VERSION 5.8 ;
BUSBITCHARS "[]" ;
DIVIDERCHAR "/" ;
UNITS
    DATABASE MICRONS 1000 ;
END UNITS

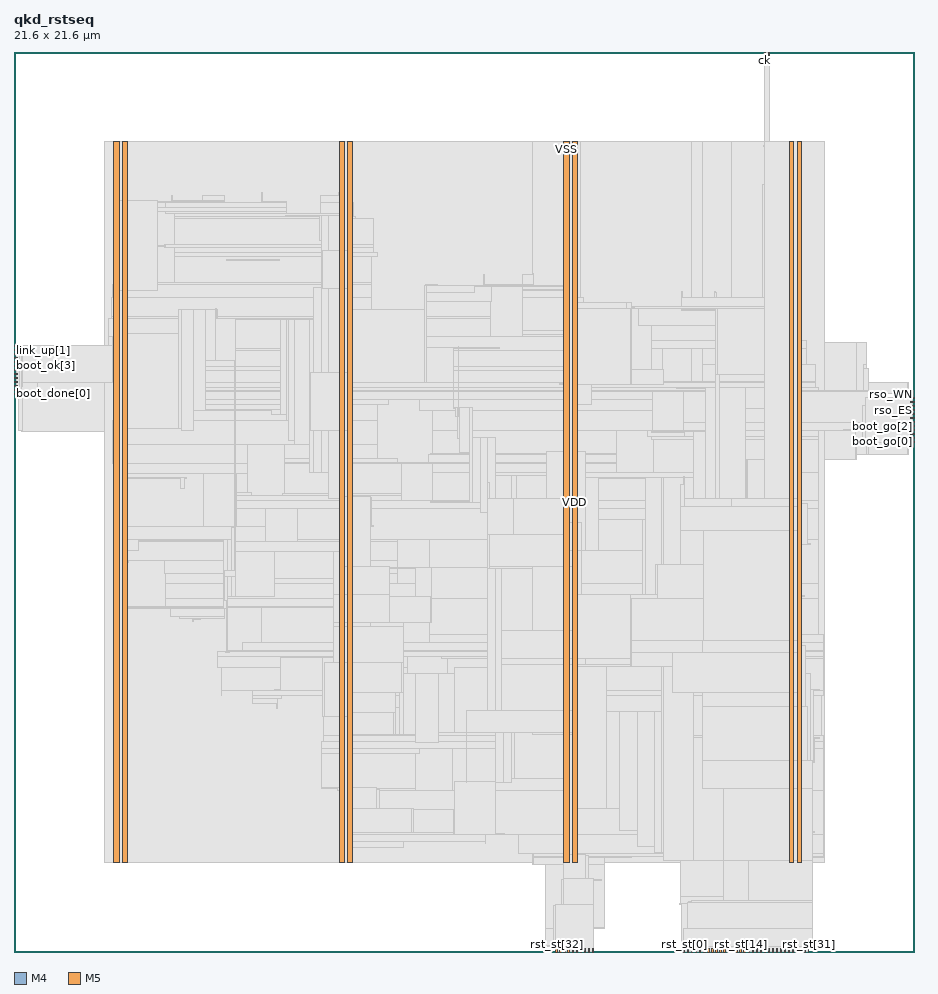
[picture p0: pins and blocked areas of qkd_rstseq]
MACRO qkd_rstseq
  FOREIGN qkd_rstseq 0 0 ;
  CLASS BLOCK ;
  SIZE 21.6 BY 21.6 ;
  PIN boot_done[0]
    DIRECTION INPUT ;
    USE SIGNAL ;
    PORT
      LAYER M4 ;
        RECT  0 13.392 0.084 13.416 ;
    END
  END boot_done[0]
  PIN boot_done[1]
    DIRECTION INPUT ;
    USE SIGNAL ;
    PORT
      LAYER M4 ;
        RECT  0 13.488 0.084 13.512 ;
    END
  END boot_done[1]
  PIN boot_done[2]
    DIRECTION INPUT ;
    USE SIGNAL ;
    PORT
      LAYER M4 ;
        RECT  0 13.584 0.084 13.608 ;
    END
  END boot_done[2]
  PIN boot_done[3]
    DIRECTION INPUT ;
    USE SIGNAL ;
    PORT
      LAYER M4 ;
        RECT  0 13.68 0.084 13.704 ;
    END
  END boot_done[3]
  PIN boot_go[0]
    DIRECTION OUTPUT ;
    USE SIGNAL ;
    PORT
      LAYER M4 ;
        RECT  21.516 12.24 21.6 12.264 ;
    END
  END boot_go[0]
  PIN boot_go[1]
    DIRECTION OUTPUT ;
    USE SIGNAL ;
    PORT
      LAYER M4 ;
        RECT  21.516 12.336 21.6 12.36 ;
    END
  END boot_go[1]
  PIN boot_go[2]
    DIRECTION OUTPUT ;
    USE SIGNAL ;
    PORT
      LAYER M4 ;
        RECT  21.516 12.432 21.6 12.456 ;
    END
  END boot_go[2]
  PIN boot_go[3]
    DIRECTION OUTPUT ;
    USE SIGNAL ;
    PORT
      LAYER M4 ;
        RECT  21.516 12.528 21.6 12.552 ;
    END
  END boot_go[3]
  PIN boot_ok[0]
    DIRECTION INPUT ;
    USE SIGNAL ;
    PORT
      LAYER M4 ;
        RECT  0 13.776 0.084 13.8 ;
    END
  END boot_ok[0]
  PIN boot_ok[1]
    DIRECTION INPUT ;
    USE SIGNAL ;
    PORT
      LAYER M4 ;
        RECT  0 13.872 0.084 13.896 ;
    END
  END boot_ok[1]
  PIN boot_ok[2]
    DIRECTION INPUT ;
    USE SIGNAL ;
    PORT
      LAYER M4 ;
        RECT  0 13.968 0.084 13.992 ;
    END
  END boot_ok[2]
  PIN boot_ok[3]
    DIRECTION INPUT ;
    USE SIGNAL ;
    PORT
      LAYER M4 ;
        RECT  0 14.064 0.084 14.088 ;
    END
  END boot_ok[3]
  PIN ck
    DIRECTION INPUT ;
    USE SIGNAL ;
    PORT
      LAYER M5 ;
        RECT  18 21.516 18.024 21.6 ;
    END
  END ck
  PIN link_up[0]
    DIRECTION INPUT ;
    USE SIGNAL ;
    PORT
      LAYER M4 ;
        RECT  0 14.16 0.084 14.184 ;
    END
  END link_up[0]
  PIN link_up[1]
    DIRECTION INPUT ;
    USE SIGNAL ;
    PORT
      LAYER M4 ;
        RECT  0 14.256 0.084 14.28 ;
    END
  END link_up[1]
  PIN link_up[2]
    DIRECTION INPUT ;
    USE SIGNAL ;
    PORT
      LAYER M4 ;
        RECT  0 14.352 0.084 14.376 ;
    END
  END link_up[2]
  PIN link_up[3]
    DIRECTION INPUT ;
    USE SIGNAL ;
    PORT
      LAYER M4 ;
        RECT  0 14.448 0.084 14.472 ;
    END
  END link_up[3]
  PIN por_n
    DIRECTION INPUT ;
    USE SIGNAL ;
    PORT
      LAYER M5 ;
        RECT  18.096 21.516 18.12 21.6 ;
    END
  END por_n
  PIN rso_EN
    DIRECTION OUTPUT ;
    USE SIGNAL ;
    PORT
      LAYER M4 ;
        RECT  21.516 12.72 21.6 12.744 ;
    END
  END rso_EN
  PIN rso_ES
    DIRECTION OUTPUT ;
    USE SIGNAL ;
    PORT
      LAYER M4 ;
        RECT  21.516 12.816 21.6 12.84 ;
    END
  END rso_ES
  PIN rso_WN
    DIRECTION OUTPUT ;
    USE SIGNAL ;
    PORT
      LAYER M4 ;
        RECT  21.516 13.2 21.6 13.224 ;
    END
  END rso_WN
  PIN rso_WS
    DIRECTION OUTPUT ;
    USE SIGNAL ;
    PORT
      LAYER M4 ;
        RECT  21.516 13.296 21.6 13.32 ;
    END
  END rso_WS
  PIN rso_c
    DIRECTION OUTPUT ;
    USE SIGNAL ;
    PORT
      LAYER M4 ;
        RECT  21.516 12.624 21.6 12.648 ;
    END
  END rso_c
  PIN rso_fwd
    DIRECTION OUTPUT ;
    USE SIGNAL ;
    PORT
      LAYER M4 ;
        RECT  21.516 12.912 21.6 12.936 ;
    END
  END rso_fwd
  PIN rso_host
    DIRECTION OUTPUT ;
    USE SIGNAL ;
    PORT
      LAYER M4 ;
        RECT  21.516 13.008 21.6 13.032 ;
    END
  END rso_host
  PIN rso_link
    DIRECTION OUTPUT ;
    USE SIGNAL ;
    PORT
      LAYER M4 ;
        RECT  21.516 13.104 21.6 13.128 ;
    END
  END rso_link
  PIN rst_st[0]
    DIRECTION OUTPUT ;
    USE SIGNAL ;
    PORT
      LAYER M5 ;
        RECT  16.08 0 16.104 0.084 ;
    END
  END rst_st[0]
  PIN rst_st[10]
    DIRECTION OUTPUT ;
    USE SIGNAL ;
    PORT
      LAYER M5 ;
        RECT  17.04 0 17.064 0.084 ;
    END
  END rst_st[10]
  PIN rst_st[11]
    DIRECTION OUTPUT ;
    USE SIGNAL ;
    PORT
      LAYER M5 ;
        RECT  17.136 0 17.16 0.084 ;
    END
  END rst_st[11]
  PIN rst_st[12]
    DIRECTION OUTPUT ;
    USE SIGNAL ;
    PORT
      LAYER M5 ;
        RECT  17.232 0 17.256 0.084 ;
    END
  END rst_st[12]
  PIN rst_st[13]
    DIRECTION OUTPUT ;
    USE SIGNAL ;
    PORT
      LAYER M5 ;
        RECT  17.328 0 17.352 0.084 ;
    END
  END rst_st[13]
  PIN rst_st[14]
    DIRECTION OUTPUT ;
    USE SIGNAL ;
    PORT
      LAYER M5 ;
        RECT  17.424 0 17.448 0.084 ;
    END
  END rst_st[14]
  PIN rst_st[15]
    DIRECTION OUTPUT ;
    USE SIGNAL ;
    PORT
      LAYER M5 ;
        RECT  17.52 0 17.544 0.084 ;
    END
  END rst_st[15]
  PIN rst_st[16]
    DIRECTION OUTPUT ;
    USE SIGNAL ;
    PORT
      LAYER M5 ;
        RECT  17.616 0 17.64 0.084 ;
    END
  END rst_st[16]
  PIN rst_st[17]
    DIRECTION OUTPUT ;
    USE SIGNAL ;
    PORT
      LAYER M5 ;
        RECT  17.712 0 17.736 0.084 ;
    END
  END rst_st[17]
  PIN rst_st[18]
    DIRECTION OUTPUT ;
    USE SIGNAL ;
    PORT
      LAYER M5 ;
        RECT  17.808 0 17.832 0.084 ;
    END
  END rst_st[18]
  PIN rst_st[19]
    DIRECTION OUTPUT ;
    USE SIGNAL ;
    PORT
      LAYER M5 ;
        RECT  17.904 0 17.928 0.084 ;
    END
  END rst_st[19]
  PIN rst_st[1]
    DIRECTION OUTPUT ;
    USE SIGNAL ;
    PORT
      LAYER M5 ;
        RECT  16.176 0 16.2 0.084 ;
    END
  END rst_st[1]
  PIN rst_st[20]
    DIRECTION OUTPUT ;
    USE SIGNAL ;
    PORT
      LAYER M5 ;
        RECT  18 0 18.024 0.084 ;
    END
  END rst_st[20]
  PIN rst_st[21]
    DIRECTION OUTPUT ;
    USE SIGNAL ;
    PORT
      LAYER M5 ;
        RECT  18.096 0 18.12 0.084 ;
    END
  END rst_st[21]
  PIN rst_st[22]
    DIRECTION OUTPUT ;
    USE SIGNAL ;
    PORT
      LAYER M5 ;
        RECT  18.192 0 18.216 0.084 ;
    END
  END rst_st[22]
  PIN rst_st[23]
    DIRECTION OUTPUT ;
    USE SIGNAL ;
    PORT
      LAYER M5 ;
        RECT  18.288 0 18.312 0.084 ;
    END
  END rst_st[23]
  PIN rst_st[24]
    DIRECTION OUTPUT ;
    USE SIGNAL ;
    PORT
      LAYER M5 ;
        RECT  18.384 0 18.408 0.084 ;
    END
  END rst_st[24]
  PIN rst_st[25]
    DIRECTION OUTPUT ;
    USE SIGNAL ;
    PORT
      LAYER M5 ;
        RECT  18.48 0 18.504 0.084 ;
    END
  END rst_st[25]
  PIN rst_st[26]
    DIRECTION OUTPUT ;
    USE SIGNAL ;
    PORT
      LAYER M5 ;
        RECT  18.576 0 18.6 0.084 ;
    END
  END rst_st[26]
  PIN rst_st[27]
    DIRECTION OUTPUT ;
    USE SIGNAL ;
    PORT
      LAYER M5 ;
        RECT  18.672 0 18.696 0.084 ;
    END
  END rst_st[27]
  PIN rst_st[28]
    DIRECTION OUTPUT ;
    USE SIGNAL ;
    PORT
      LAYER M5 ;
        RECT  18.768 0 18.792 0.084 ;
    END
  END rst_st[28]
  PIN rst_st[29]
    DIRECTION OUTPUT ;
    USE SIGNAL ;
    PORT
      LAYER M5 ;
        RECT  18.864 0 18.888 0.084 ;
    END
  END rst_st[29]
  PIN rst_st[2]
    DIRECTION OUTPUT ;
    USE SIGNAL ;
    PORT
      LAYER M5 ;
        RECT  16.272 0 16.296 0.084 ;
    END
  END rst_st[2]
  PIN rst_st[30]
    DIRECTION OUTPUT ;
    USE SIGNAL ;
    PORT
      LAYER M5 ;
        RECT  18.96 0 18.984 0.084 ;
    END
  END rst_st[30]
  PIN rst_st[31]
    DIRECTION OUTPUT ;
    USE SIGNAL ;
    PORT
      LAYER M5 ;
        RECT  19.056 0 19.08 0.084 ;
    END
  END rst_st[31]
  PIN rst_st[32]
    DIRECTION OUTPUT ;
    USE SIGNAL ;
    PORT
      LAYER M5 ;
        RECT  13.008 0 13.032 0.084 ;
    END
  END rst_st[32]
  PIN rst_st[33]
    DIRECTION OUTPUT ;
    USE SIGNAL ;
    PORT
      LAYER M5 ;
        RECT  13.104 0 13.128 0.084 ;
    END
  END rst_st[33]
  PIN rst_st[34]
    DIRECTION OUTPUT ;
    USE SIGNAL ;
    PORT
      LAYER M5 ;
        RECT  13.2 0 13.224 0.084 ;
    END
  END rst_st[34]
  PIN rst_st[35]
    DIRECTION OUTPUT ;
    USE SIGNAL ;
    PORT
      LAYER M5 ;
        RECT  13.296 0 13.32 0.084 ;
    END
  END rst_st[35]
  PIN rst_st[36]
    DIRECTION OUTPUT ;
    USE SIGNAL ;
    PORT
      LAYER M5 ;
        RECT  13.392 0 13.416 0.084 ;
    END
  END rst_st[36]
  PIN rst_st[37]
    DIRECTION OUTPUT ;
    USE SIGNAL ;
    PORT
      LAYER M5 ;
        RECT  13.488 0 13.512 0.084 ;
    END
  END rst_st[37]
  PIN rst_st[38]
    DIRECTION OUTPUT ;
    USE SIGNAL ;
    PORT
      LAYER M5 ;
        RECT  13.584 0 13.608 0.084 ;
    END
  END rst_st[38]
  PIN rst_st[39]
    DIRECTION OUTPUT ;
    USE SIGNAL ;
    PORT
      LAYER M5 ;
        RECT  13.68 0 13.704 0.084 ;
    END
  END rst_st[39]
  PIN rst_st[3]
    DIRECTION OUTPUT ;
    USE SIGNAL ;
    PORT
      LAYER M5 ;
        RECT  16.368 0 16.392 0.084 ;
    END
  END rst_st[3]
  PIN rst_st[40]
    DIRECTION OUTPUT ;
    USE SIGNAL ;
    PORT
      LAYER M5 ;
        RECT  13.776 0 13.8 0.084 ;
    END
  END rst_st[40]
  PIN rst_st[41]
    DIRECTION OUTPUT ;
    USE SIGNAL ;
    PORT
      LAYER M5 ;
        RECT  13.872 0 13.896 0.084 ;
    END
  END rst_st[41]
  PIN rst_st[4]
    DIRECTION OUTPUT ;
    USE SIGNAL ;
    PORT
      LAYER M5 ;
        RECT  16.464 0 16.488 0.084 ;
    END
  END rst_st[4]
  PIN rst_st[5]
    DIRECTION OUTPUT ;
    USE SIGNAL ;
    PORT
      LAYER M5 ;
        RECT  16.56 0 16.584 0.084 ;
    END
  END rst_st[5]
  PIN rst_st[6]
    DIRECTION OUTPUT ;
    USE SIGNAL ;
    PORT
      LAYER M5 ;
        RECT  16.656 0 16.68 0.084 ;
    END
  END rst_st[6]
  PIN rst_st[7]
    DIRECTION OUTPUT ;
    USE SIGNAL ;
    PORT
      LAYER M5 ;
        RECT  16.752 0 16.776 0.084 ;
    END
  END rst_st[7]
  PIN rst_st[8]
    DIRECTION OUTPUT ;
    USE SIGNAL ;
    PORT
      LAYER M5 ;
        RECT  16.848 0 16.872 0.084 ;
    END
  END rst_st[8]
  PIN rst_st[9]
    DIRECTION OUTPUT ;
    USE SIGNAL ;
    PORT
      LAYER M5 ;
        RECT  16.944 0 16.968 0.084 ;
    END
  END rst_st[9]
  PIN soft_rst
    DIRECTION INPUT ;
    USE SIGNAL ;
    PORT
      LAYER M4 ;
        RECT  0 14.544 0.084 14.568 ;
    END
  END soft_rst
  PIN VDD
    DIRECTION INOUT ;
    USE POWER ;
    PORT
      LAYER M5 ;
        RECT  18.792 2.151 18.912 19.449 ;
        RECT  13.392 2.151 13.512 19.449 ;
        RECT  7.992 2.151 8.112 19.449 ;
        RECT  2.592 2.151 2.712 19.449 ;
    END
  END VDD
  PIN VSS
    DIRECTION INOUT ;
    USE GROUND ;
    PORT
      LAYER M5 ;
        RECT  18.6 2.137 18.72 19.463 ;
        RECT  13.2 2.137 13.32 19.463 ;
        RECT  7.8 2.137 7.92 19.463 ;
        RECT  2.4 2.137 2.52 19.463 ;
    END
  END VSS
  # OT_OBS_CLOSED layer=M5 d_um=1.536 added=25
  OBS
    LAYER RVTN ;
     RECT  2.16 2.16 19.44 2.295 ;
     RECT  2.16 2.565 19.44 2.835 ;
     RECT  2.16 3.105 19.44 3.375 ;
     RECT  2.16 3.645 19.44 3.915 ;
     RECT  2.16 4.185 19.44 4.455 ;
     RECT  2.16 4.725 19.44 4.995 ;
     RECT  2.16 5.265 19.44 5.535 ;
     RECT  2.16 5.805 19.44 6.075 ;
     RECT  2.16 6.345 19.44 6.615 ;
     RECT  2.16 6.885 19.44 7.155 ;
     RECT  2.16 7.425 19.44 7.695 ;
     RECT  2.16 7.965 19.44 8.235 ;
     RECT  2.16 8.505 19.44 8.775 ;
     RECT  2.16 9.045 19.44 9.315 ;
     RECT  2.16 9.585 19.44 9.855 ;
     RECT  2.16 10.125 19.44 10.395 ;
     RECT  2.16 10.665 19.44 10.935 ;
     RECT  2.16 11.205 19.44 11.475 ;
     RECT  2.16 11.745 19.44 12.015 ;
     RECT  2.16 12.285 19.44 12.555 ;
     RECT  2.16 12.825 19.44 13.095 ;
     RECT  2.16 13.365 19.44 13.635 ;
     RECT  2.16 13.905 19.44 14.175 ;
     RECT  2.16 14.445 19.44 14.715 ;
     RECT  2.16 14.985 19.44 15.255 ;
     RECT  2.16 15.525 19.44 15.795 ;
     RECT  2.16 16.065 19.44 16.335 ;
     RECT  2.16 16.605 19.44 16.875 ;
     RECT  2.16 17.145 19.44 17.415 ;
     RECT  2.16 17.685 19.44 17.955 ;
     RECT  2.16 18.225 19.44 18.495 ;
     RECT  2.16 18.765 19.44 19.035 ;
     RECT  2.16 19.305 19.44 19.44 ;
    LAYER RVTP ;
     RECT  2.16 2.295 19.44 2.565 ;
     RECT  2.16 2.835 19.44 3.105 ;
     RECT  2.16 3.375 19.44 3.645 ;
     RECT  2.16 3.915 19.44 4.185 ;
     RECT  2.16 4.455 19.44 4.725 ;
     RECT  2.16 4.995 19.44 5.265 ;
     RECT  2.16 5.535 19.44 5.805 ;
     RECT  2.16 6.075 19.44 6.345 ;
     RECT  2.16 6.615 19.44 6.885 ;
     RECT  2.16 7.155 19.44 7.425 ;
     RECT  2.16 7.695 19.44 7.965 ;
     RECT  2.16 8.235 19.44 8.505 ;
     RECT  2.16 8.775 19.44 9.045 ;
     RECT  2.16 9.315 19.44 9.585 ;
     RECT  2.16 9.855 19.44 10.125 ;
     RECT  2.16 10.395 19.44 10.665 ;
     RECT  2.16 10.935 19.44 11.205 ;
     RECT  2.16 11.475 19.44 11.745 ;
     RECT  2.16 12.015 19.44 12.285 ;
     RECT  2.16 12.555 19.44 12.825 ;
     RECT  2.16 13.095 19.44 13.365 ;
     RECT  2.16 13.635 19.44 13.905 ;
     RECT  2.16 14.175 19.44 14.445 ;
     RECT  2.16 14.715 19.44 14.985 ;
     RECT  2.16 15.255 19.44 15.525 ;
     RECT  2.16 15.795 19.44 16.065 ;
     RECT  2.16 16.335 19.44 16.605 ;
     RECT  2.16 16.875 19.44 17.145 ;
     RECT  2.16 17.415 19.44 17.685 ;
     RECT  2.16 17.955 19.44 18.225 ;
     RECT  2.16 18.495 19.44 18.765 ;
     RECT  2.16 19.035 19.44 19.305 ;
    LAYER M1 ;
     RECT  2.16 2.151 19.44 19.449 ;
    LAYER M2 ;
     RECT  0.103 12.528 0.139 12.546 ;
     RECT  0.139 12.528 0.175 13.05 ;
     RECT  0.175 12.492 0.211 13.05 ;
     RECT  0.103 14.112 0.211 14.13 ;
     RECT  0.211 12.492 2.16 14.13 ;
     RECT  2.16 2.151 12.451 19.449 ;
     RECT  12.451 2.106 13.595 19.449 ;
     RECT  13.595 2.151 16.267 19.449 ;
     RECT  16.267 2.034 16.519 19.449 ;
     RECT  16.519 1.881 17.231 19.449 ;
     RECT  17.231 2.106 18.527 19.449 ;
     RECT  18.527 2.151 19.44 19.449 ;
     RECT  19.44 11.826 20.219 14.634 ;
     RECT  20.219 11.952 20.471 14.634 ;
     RECT  20.471 11.952 20.507 14.004 ;
     RECT  20.507 11.952 21.479 12.546 ;
     RECT  20.507 13.41 21.479 13.662 ;
     RECT  21.479 13.41 21.515 13.428 ;
    LAYER M3 ;
     RECT  13.032 0.091 13.05 0.139 ;
     RECT  16.02 0.091 16.974 0.523 ;
     RECT  12.744 0.139 13.05 0.571 ;
     RECT  16.02 0.523 17.91 0.571 ;
     RECT  19.008 0.091 19.026 0.571 ;
     RECT  16.02 0.571 19.026 1.147 ;
     RECT  15.984 1.147 19.026 1.339 ;
     RECT  12.744 0.571 14.166 2.101 ;
     RECT  15.984 1.339 19.098 2.203 ;
     RECT  12.456 2.101 14.166 2.263 ;
     RECT  15.588 2.203 19.098 2.263 ;
     RECT  12.456 2.263 14.814 2.299 ;
     RECT  15.588 2.263 19.422 2.299 ;
     RECT  12.456 2.299 19.422 2.371 ;
     RECT  2.415 2.143 2.505 2.413 ;
     RECT  7.815 2.143 7.905 2.413 ;
     RECT  7.815 2.413 8.097 2.497 ;
     RECT  7.815 2.497 9.342 2.641 ;
     RECT  11.304 2.605 11.322 2.641 ;
     RECT  7.815 2.641 11.322 2.827 ;
     RECT  12.096 2.371 19.422 2.827 ;
     RECT  7.815 2.827 19.422 3.875 ;
     RECT  7.815 3.875 9.63 3.883 ;
     RECT  7.776 3.883 9.63 3.931 ;
     RECT  7.38 3.931 9.63 4.765 ;
     RECT  7.38 4.765 9.738 4.891 ;
     RECT  10.512 3.875 19.422 4.891 ;
     RECT  7.38 4.891 19.422 5.063 ;
     RECT  7.416 5.063 19.422 5.189 ;
     RECT  6.3 5.845 6.318 5.971 ;
     RECT  5.724 5.971 6.318 6.079 ;
     RECT  5.724 6.079 6.426 6.151 ;
     RECT  7.416 5.189 19.386 6.151 ;
     RECT  5.724 6.151 19.422 6.269 ;
     RECT  4.968 6.151 4.986 6.277 ;
     RECT  5.724 6.269 9.45 6.277 ;
     RECT  4.968 6.277 9.45 6.817 ;
     RECT  10.404 6.269 19.422 7.051 ;
     RECT  4.896 6.817 9.45 7.087 ;
     RECT  10.26 7.051 19.422 7.087 ;
     RECT  4.896 7.087 19.422 7.223 ;
     RECT  5.112 7.223 19.422 7.229 ;
     RECT  5.472 7.229 19.422 7.421 ;
     RECT  9.972 7.421 19.422 7.619 ;
     RECT  4.284 7.933 4.302 7.969 ;
     RECT  4.284 7.969 4.482 8.005 ;
     RECT  3.96 8.005 5.058 8.041 ;
     RECT  3.744 8.041 5.058 8.239 ;
     RECT  2.415 2.413 2.697 8.251 ;
     RECT  3.636 8.239 5.058 8.251 ;
     RECT  2.415 8.251 5.058 8.275 ;
     RECT  5.94 7.421 9.162 8.275 ;
     RECT  2.415 8.275 9.162 8.303 ;
     RECT  3.636 8.303 9.162 8.491 ;
     RECT  9.972 7.619 19.314 8.491 ;
     RECT  3.636 8.491 19.314 8.843 ;
     RECT  3.636 8.843 9.198 9.085 ;
     RECT  2.415 8.303 2.697 9.355 ;
     RECT  2.415 9.355 2.754 9.391 ;
     RECT  3.6 9.085 9.198 9.391 ;
     RECT  2.415 9.391 9.198 9.851 ;
     RECT  6.804 9.851 9.198 9.895 ;
     RECT  9.972 8.843 19.314 9.895 ;
     RECT  2.415 9.851 6.03 10.205 ;
     RECT  5.328 10.205 6.03 10.633 ;
     RECT  6.804 9.895 19.314 10.633 ;
     RECT  5.328 10.633 19.314 10.829 ;
     RECT  5.328 10.829 9.306 10.967 ;
     RECT  6.444 10.967 9.306 11.003 ;
     RECT  5.328 10.967 5.706 11.039 ;
     RECT  2.415 10.205 4.554 11.479 ;
     RECT  5.328 11.039 5.598 11.479 ;
     RECT  10.044 10.829 19.314 11.507 ;
     RECT  2.415 11.479 5.598 11.713 ;
     RECT  6.48 11.003 9.306 11.713 ;
     RECT  10.044 11.507 14.454 11.713 ;
     RECT  6.48 11.713 14.454 11.741 ;
     RECT  6.48 11.741 9.198 11.849 ;
     RECT  9.936 11.741 14.454 11.939 ;
     RECT  10.008 11.939 14.454 11.975 ;
     RECT  2.376 11.713 5.598 12.181 ;
     RECT  6.48 11.849 8.73 12.181 ;
     RECT  15.336 11.507 19.314 12.289 ;
     RECT  21.456 11.947 21.474 12.331 ;
     RECT  15.3 12.289 19.314 12.361 ;
     RECT  15.192 12.361 19.314 12.509 ;
     RECT  0.18 12.487 0.198 12.523 ;
     RECT  10.044 11.975 14.454 12.523 ;
     RECT  15.192 12.509 15.318 12.523 ;
     RECT  16.056 12.509 19.314 12.523 ;
     RECT  20.196 11.821 20.214 12.523 ;
     RECT  16.056 12.523 20.214 12.712 ;
     RECT  2.376 12.181 8.73 12.749 ;
     RECT  10.044 12.523 15.318 12.991 ;
     RECT  2.415 12.749 8.73 13.135 ;
     RECT  2.415 13.135 8.982 13.261 ;
     RECT  9.72 12.991 15.318 13.261 ;
     RECT  0.108 12.523 0.198 13.333 ;
     RECT  21.456 12.331 21.51 13.433 ;
     RECT  2.415 13.261 15.318 13.441 ;
     RECT  16.056 12.712 20.502 13.441 ;
     RECT  2.415 13.441 20.502 13.469 ;
     RECT  2.415 13.469 19.314 13.559 ;
     RECT  2.415 13.559 19.242 13.667 ;
     RECT  21.456 13.433 21.474 13.667 ;
     RECT  2.415 13.667 14.562 13.675 ;
     RECT  15.3 13.667 19.242 13.703 ;
     RECT  0.108 13.333 0.558 13.901 ;
     RECT  2.34 13.675 14.562 13.963 ;
     RECT  20.376 13.469 20.502 14.009 ;
     RECT  2.304 13.963 14.562 14.059 ;
     RECT  16.524 13.703 19.242 14.099 ;
     RECT  20.376 14.009 20.466 14.099 ;
     RECT  0.108 13.901 0.126 14.381 ;
     RECT  2.268 14.059 14.562 14.429 ;
     RECT  15.3 13.703 15.57 14.485 ;
     RECT  16.524 14.099 19.026 14.485 ;
     RECT  20.448 14.099 20.466 14.639 ;
     RECT  15.3 14.485 19.026 14.675 ;
     RECT  2.268 14.429 14.13 14.783 ;
     RECT  12.204 14.783 14.13 14.819 ;
     RECT  12.204 14.819 13.77 14.909 ;
     RECT  15.3 14.675 18.897 15.025 ;
     RECT  2.268 14.783 11.43 15.215 ;
     RECT  2.34 15.215 11.43 15.251 ;
     RECT  14.976 15.025 18.897 15.448 ;
     RECT  14.832 15.448 18.897 15.485 ;
     RECT  9.864 15.251 11.43 15.601 ;
     RECT  2.34 15.251 8.586 15.719 ;
     RECT  12.204 14.909 13.662 15.719 ;
     RECT  16.02 15.485 18.897 15.719 ;
     RECT  16.812 15.719 16.866 15.827 ;
     RECT  16.02 15.719 16.038 15.863 ;
     RECT  16.812 15.827 16.83 15.863 ;
     RECT  9.864 15.601 11.466 15.979 ;
     RECT  12.204 15.719 13.497 15.979 ;
     RECT  9.864 15.979 13.497 15.989 ;
     RECT  9.864 15.989 10.17 16.013 ;
     RECT  2.376 15.719 8.586 16.025 ;
     RECT  10.152 16.013 10.17 16.025 ;
     RECT  11.268 15.989 12.474 16.025 ;
     RECT  2.415 16.025 8.586 16.061 ;
     RECT  2.415 16.061 2.754 16.169 ;
     RECT  11.268 16.025 11.286 16.259 ;
     RECT  12.204 16.025 12.474 16.259 ;
     RECT  12.456 16.259 12.474 16.295 ;
     RECT  3.852 16.061 8.586 16.681 ;
     RECT  3.852 16.681 8.73 16.799 ;
     RECT  3.852 16.799 8.622 16.915 ;
     RECT  3.6 16.915 8.622 16.973 ;
     RECT  3.852 16.973 8.622 17.609 ;
     RECT  3.852 17.609 8.19 17.645 ;
     RECT  3.852 17.645 8.154 17.717 ;
     RECT  3.852 17.717 6.534 17.725 ;
     RECT  3.636 17.725 6.534 17.761 ;
     RECT  3.42 17.761 6.534 17.879 ;
     RECT  3.636 17.879 6.534 17.987 ;
     RECT  7.344 17.717 8.154 17.987 ;
     RECT  2.415 16.169 2.697 17.989 ;
     RECT  3.636 17.987 5.058 18.023 ;
     RECT  5.94 17.987 6.534 18.023 ;
     RECT  2.415 17.989 2.862 18.029 ;
     RECT  3.78 18.023 5.058 18.032 ;
     RECT  3.78 18.032 3.798 18.149 ;
     RECT  4.536 18.032 5.058 18.149 ;
     RECT  7.344 17.987 8.097 18.149 ;
     RECT  5.94 18.023 5.958 18.221 ;
     RECT  7.776 18.149 8.097 18.221 ;
     RECT  17.964 15.719 18.897 18.419 ;
     RECT  2.415 18.029 2.697 19.187 ;
     RECT  7.815 18.221 8.097 19.187 ;
     RECT  13.215 15.989 13.497 19.187 ;
     RECT  18.144 18.419 18.897 19.187 ;
     RECT  18.144 19.187 18.705 19.339 ;
     RECT  18 19.339 18.705 19.379 ;
     RECT  2.415 19.187 2.505 19.457 ;
     RECT  7.815 19.187 7.905 19.457 ;
     RECT  13.215 19.187 13.305 19.457 ;
     RECT  18.615 19.379 18.705 19.457 ;
    LAYER M4 ;
     RECT  0.06 13.392 0.137 14.568 ;
     RECT  0.137 13.488 0.173 14.568 ;
     RECT  0.173 13.584 0.209 14.568 ;
     RECT  0.209 13.68 2.365 14.568 ;
     RECT  2.365 12.576 2.408 12.6 ;
     RECT  2.365 13.68 2.408 14.76 ;
     RECT  2.408 2.148 2.512 19.452 ;
     RECT  2.512 2.418 2.704 19.182 ;
     RECT  2.704 9.648 2.981 9.912 ;
     RECT  2.704 15.888 3.443 15.912 ;
     RECT  2.704 16.944 3.629 16.968 ;
     RECT  2.704 12.576 3.949 14.856 ;
     RECT  2.704 11.376 3.985 11.4 ;
     RECT  3.949 12.576 4.021 15.432 ;
     RECT  3.985 11.136 4.097 11.4 ;
     RECT  4.097 11.376 4.133 11.4 ;
     RECT  2.704 18 4.277 18.024 ;
     RECT  4.021 12.528 4.313 15.432 ;
     RECT  4.313 13.008 4.601 15.432 ;
     RECT  4.601 14.208 4.889 15.432 ;
     RECT  2.704 8.256 5.029 8.28 ;
     RECT  2.981 9.888 5.029 9.912 ;
     RECT  5.029 8.256 5.123 9.912 ;
     RECT  5.077 7.2 5.164 7.224 ;
     RECT  5.123 8.544 5.228 9.912 ;
     RECT  5.228 8.544 5.315 10.2 ;
     RECT  4.601 13.008 6.181 13.032 ;
     RECT  5.315 8.544 6.257 9.624 ;
     RECT  5.101 16.608 6.365 16.632 ;
     RECT  6.253 6.288 6.397 6.312 ;
     RECT  6.181 12.912 6.397 13.032 ;
     RECT  4.889 14.496 6.397 15.192 ;
     RECT  6.397 12.912 6.541 15.192 ;
     RECT  6.541 12.768 6.577 15.192 ;
     RECT  6.577 12.288 6.721 15.192 ;
     RECT  6.721 12.192 7.081 15.192 ;
     RECT  7.081 11.52 7.189 15.192 ;
     RECT  6.505 17.664 7.333 17.688 ;
     RECT  7.189 11.52 7.381 15.96 ;
     RECT  7.333 17.088 7.381 17.688 ;
     RECT  6.397 6.288 7.405 7.08 ;
     RECT  7.381 11.52 7.549 17.688 ;
     RECT  7.405 5.664 7.669 7.08 ;
     RECT  6.257 8.976 7.669 9.624 ;
     RECT  7.369 3.936 7.765 3.96 ;
     RECT  7.765 3.888 7.808 3.96 ;
     RECT  7.669 5.664 7.808 9.624 ;
     RECT  7.549 10.896 7.808 17.688 ;
     RECT  7.808 2.148 7.912 19.452 ;
     RECT  7.912 2.418 8.104 19.182 ;
     RECT  8.104 6.912 8.579 9.24 ;
     RECT  8.104 10.224 8.579 10.92 ;
     RECT  8.579 10.224 8.633 10.248 ;
     RECT  8.104 3.408 8.705 3.96 ;
     RECT  8.705 3.408 8.777 3.912 ;
     RECT  8.777 3.408 9.097 3.432 ;
     RECT  8.579 6.912 9.173 7.944 ;
     RECT  8.104 5.232 9.241 5.88 ;
     RECT  9.173 6.912 9.241 6.936 ;
     RECT  9.241 5.232 9.347 6.936 ;
     RECT  9.097 3.264 9.541 3.432 ;
     RECT  9.347 5.232 9.637 6.696 ;
     RECT  9.173 7.92 9.637 7.944 ;
     RECT  8.579 9.216 9.637 9.24 ;
     RECT  8.104 13.68 9.853 15.432 ;
     RECT  9.853 13.68 9.893 16.008 ;
     RECT  9.637 7.92 10.019 9.24 ;
     RECT  9.637 5.04 10.181 6.696 ;
     RECT  9.541 2.88 10.537 3.432 ;
     RECT  9.893 13.68 10.537 14.52 ;
     RECT  10.537 13.056 10.541 14.52 ;
     RECT  10.537 2.832 10.573 3.432 ;
     RECT  10.181 5.28 10.573 6.696 ;
     RECT  10.541 13.056 10.604 13.08 ;
     RECT  10.604 12.864 10.645 13.08 ;
     RECT  10.645 12.336 10.681 13.08 ;
     RECT  9.997 10.8 10.933 10.824 ;
     RECT  10.681 12 10.933 13.08 ;
     RECT  10.933 10.8 11.009 13.08 ;
     RECT  9.893 15.84 11.045 16.008 ;
     RECT  11.009 10.8 11.185 12.36 ;
     RECT  10.573 5.28 11.365 6.84 ;
     RECT  10.019 8.496 11.365 9.24 ;
     RECT  11.185 10.56 11.365 12.36 ;
     RECT  10.573 2.832 11.545 4.104 ;
     RECT  11.365 5.28 11.545 9.24 ;
     RECT  11.545 2.832 11.549 9.24 ;
     RECT  11.365 10.368 11.549 12.36 ;
     RECT  10.541 14.496 11.657 14.52 ;
     RECT  11.045 15.984 11.657 16.008 ;
     RECT  11.549 4.08 11.747 9.24 ;
     RECT  11.549 2.832 11.765 2.856 ;
     RECT  11.747 8.496 11.941 9.24 ;
     RECT  11.549 10.368 11.941 11.448 ;
     RECT  11.747 4.08 11.945 7.464 ;
     RECT  11.941 8.496 11.945 11.448 ;
     RECT  11.945 4.176 12.017 7.464 ;
     RECT  11.945 9.12 12.053 11.448 ;
     RECT  12.053 10.368 12.769 11.448 ;
     RECT  12.733 0.144 12.956 0.168 ;
     RECT  12.956 0.144 13.021 1.128 ;
     RECT  13.021 0.096 13.129 1.128 ;
     RECT  13.129 0.096 13.139 1.752 ;
     RECT  13.139 0.144 13.208 1.752 ;
     RECT  12.017 4.176 13.208 5.784 ;
     RECT  12.017 6.912 13.208 7.464 ;
     RECT  12.053 9.216 13.208 9.24 ;
     RECT  12.769 10.368 13.208 12.024 ;
     RECT  13.093 13.632 13.208 13.656 ;
     RECT  12.229 15.888 13.208 15.912 ;
     RECT  13.208 0.144 13.249 19.452 ;
     RECT  13.249 1.728 13.312 19.452 ;
     RECT  13.312 1.728 13.504 19.182 ;
     RECT  13.249 0.144 13.523 0.6 ;
     RECT  13.504 9.648 13.709 12.024 ;
     RECT  13.504 1.728 13.781 2.328 ;
     RECT  13.504 13.152 13.853 14.424 ;
     RECT  13.709 9.648 14.033 11.4 ;
     RECT  13.781 1.728 14.105 1.752 ;
     RECT  13.523 0.576 14.177 0.6 ;
     RECT  13.504 3.456 14.213 8.568 ;
     RECT  14.213 3.456 14.533 5.784 ;
     RECT  13.853 13.632 14.819 14.424 ;
     RECT  14.677 15.456 14.819 15.576 ;
     RECT  14.819 15.456 14.88 15.48 ;
     RECT  14.533 2.928 14.965 5.784 ;
     RECT  14.213 6.864 15.073 8.568 ;
     RECT  14.033 9.648 15.073 10.392 ;
     RECT  15.073 6.864 15.145 10.392 ;
     RECT  14.033 11.376 15.145 11.4 ;
     RECT  14.965 2.544 15.361 5.784 ;
     RECT  15.361 2.4 15.541 5.784 ;
     RECT  15.145 6.864 15.541 11.4 ;
     RECT  15.541 2.4 15.577 11.4 ;
     RECT  14.819 13.632 15.581 13.992 ;
     RECT  16.009 0.096 16.028 0.12 ;
     RECT  15.973 1.152 16.028 1.176 ;
     RECT  15.289 12.48 16.081 12.504 ;
     RECT  16.028 0.096 16.189 1.176 ;
     RECT  15.577 2.208 16.297 11.4 ;
     RECT  16.081 12.384 16.297 12.504 ;
     RECT  16.297 2.208 16.301 12.504 ;
     RECT  16.301 6.336 16.585 12.504 ;
     RECT  15.901 13.536 16.585 13.56 ;
     RECT  16.585 6.336 16.837 13.56 ;
     RECT  16.009 15.408 16.883 15.432 ;
     RECT  16.837 6.336 16.924 13.896 ;
     RECT  16.189 0.096 17.363 1.224 ;
     RECT  16.301 2.208 17.549 5.16 ;
     RECT  16.924 6.336 17.549 13.56 ;
     RECT  17.363 0.528 17.555 1.224 ;
     RECT  17.549 2.208 17.561 13.56 ;
     RECT  17.561 2.208 17.585 11.832 ;
     RECT  17.585 1.728 17.603 11.832 ;
     RECT  17.603 1.728 17.669 4.584 ;
     RECT  17.555 0.528 18.469 0.6 ;
     RECT  17.603 5.712 18.565 11.832 ;
     RECT  17.669 2.016 18.608 4.584 ;
     RECT  18.565 5.712 18.608 11.976 ;
     RECT  17.561 13.056 18.608 13.56 ;
     RECT  17.989 19.344 18.608 19.368 ;
     RECT  18.608 2.016 18.712 19.452 ;
     RECT  18.712 2.016 18.716 19.182 ;
     RECT  18.469 0.096 18.853 0.6 ;
     RECT  18.716 1.728 18.853 19.182 ;
     RECT  18.853 0.096 18.904 19.182 ;
     RECT  18.904 0.096 18.965 1.464 ;
     RECT  18.904 8.544 18.965 8.568 ;
     RECT  18.904 4.56 19.001 7.368 ;
     RECT  18.965 1.296 19.026 1.464 ;
     RECT  18.965 0.096 19.037 0.168 ;
     RECT  18.904 9.792 19.037 10.776 ;
     RECT  19.026 1.344 19.043 1.464 ;
     RECT  19.043 1.344 19.109 1.368 ;
     RECT  19.001 4.56 19.109 6.696 ;
     RECT  19.037 9.792 19.109 9.816 ;
     RECT  19.109 4.56 19.181 6.312 ;
     RECT  19.037 0.144 19.187 0.168 ;
     RECT  18.904 2.88 19.217 2.904 ;
     RECT  19.181 4.56 19.217 5.16 ;
     RECT  19.217 5.136 19.325 5.16 ;
     RECT  19.181 6.288 19.325 6.312 ;
     RECT  19.897 12.528 20.185 12.552 ;
     RECT  20.185 12.24 20.365 12.552 ;
     RECT  20.365 12.24 20.437 13.128 ;
     RECT  20.437 12.24 21.564 13.32 ;
    LAYER M5 ;
     RECT  16.08 0.016 19.08 0.133 ;
     RECT  16.08 0.133 19.176 0.563 ;
     RECT  13.008 0.016 13.896 1.139 ;
     RECT  16.176 0.563 19.176 1.187 ;
     RECT  16.272 1.187 19.176 1.235 ;
     RECT  13.2 1.139 13.896 1.763 ;
     RECT  2.4 2.137 2.52 2.151 ;
     RECT  7.8 2.137 7.92 2.151 ;
     RECT  17.616 1.235 19.176 2.197 ;
     RECT  13.2 1.763 13.704 2.339 ;
     RECT  9.552 2.869 9.576 3.443 ;
     RECT  17.04 2.197 19.176 3.925 ;
     RECT  16.512 3.925 19.176 4.595 ;
     RECT  13.2 2.339 13.512 5.221 ;
     RECT  10.848 4.069 10.872 5.269 ;
     RECT  12.432 5.221 13.512 5.269 ;
     RECT  7.8 2.151 8.112 5.653 ;
     RECT  9.12 5.221 9.144 5.747 ;
     RECT  10.848 5.269 13.512 5.795 ;
     RECT  16.512 4.595 19.032 5.891 ;
     RECT  16.512 5.891 18.912 6.229 ;
     RECT  11.712 5.795 13.512 6.901 ;
     RECT  7.44 5.653 8.112 6.947 ;
     RECT  9.312 6.229 9.336 6.947 ;
     RECT  11.712 6.901 13.704 7.043 ;
     RECT  15.792 6.229 18.912 7.187 ;
     RECT  16.512 7.187 18.912 7.475 ;
     RECT  11.712 7.043 13.512 7.715 ;
     RECT  7.68 6.947 8.112 7.813 ;
     RECT  7.68 7.813 8.568 7.909 ;
     RECT  5.088 7.189 5.112 8.437 ;
     RECT  14.784 6.853 14.808 8.485 ;
     RECT  9.984 7.909 10.008 8.531 ;
     RECT  7.68 7.909 9 8.579 ;
     RECT  14.784 8.485 15.432 8.579 ;
     RECT  5.04 8.437 5.112 9.013 ;
     RECT  5.04 9.013 5.304 9.155 ;
     RECT  7.8 8.579 9 9.251 ;
     RECT  12.432 7.715 13.512 9.251 ;
     RECT  15.408 8.579 15.432 9.299 ;
     RECT  13.2 9.251 13.512 9.637 ;
     RECT  11.376 9.205 11.4 10.021 ;
     RECT  16.56 7.475 18.912 10.117 ;
     RECT  13.2 9.637 13.608 10.307 ;
     RECT  15.984 10.117 18.912 10.691 ;
     RECT  11.376 10.021 11.976 10.883 ;
     RECT  17.232 10.691 18.912 10.883 ;
     RECT  7.8 9.251 8.568 10.931 ;
     RECT  15.984 10.691 16.104 11.219 ;
     RECT  11.376 10.883 11.4 11.267 ;
     RECT  16.08 11.219 16.104 11.411 ;
     RECT  7.8 10.931 8.112 12.517 ;
     RECT  7.104 12.517 8.112 13.907 ;
     RECT  5.28 9.155 5.304 14.197 ;
     RECT  10.656 12.853 10.68 14.531 ;
     RECT  4.848 14.197 5.304 15.203 ;
     RECT  4.848 15.203 4.872 15.443 ;
     RECT  16.848 13.861 16.872 15.443 ;
     RECT  14.784 13.621 14.808 15.445 ;
     RECT  14.688 15.445 14.808 15.587 ;
     RECT  2.4 2.151 2.712 15.877 ;
     RECT  7.8 13.907 8.112 15.925 ;
     RECT  7.392 15.925 8.112 16.835 ;
     RECT  2.4 15.877 3.432 18.035 ;
     RECT  2.4 18.035 2.712 19.449 ;
     RECT  7.8 16.835 8.112 19.449 ;
     RECT  13.2 10.307 13.512 19.449 ;
     RECT  18 10.883 18.912 19.449 ;
     RECT  2.4 19.449 2.52 19.463 ;
     RECT  7.8 19.449 7.92 19.463 ;
     RECT  13.2 19.449 13.32 19.463 ;
     RECT  18 19.449 18.72 19.463 ;
     RECT  18 19.463 18.12 21.584 ;
     RECT  17.04 1.235 17.616 2.197 ;
     RECT  8.112 2.869 9.552 3.443 ;
     RECT  8.112 5.221 9.12 5.747 ;
     RECT  8.112 5.747 9.144 6.229 ;
     RECT  8.112 6.229 9.312 6.947 ;
     RECT  13.512 6.853 14.784 6.901 ;
     RECT  14.808 6.853 15.792 7.187 ;
     RECT  13.704 6.901 14.784 7.043 ;
     RECT  8.112 6.947 9.336 7.813 ;
     RECT  13.512 7.043 14.784 8.579 ;
     RECT  14.808 7.187 16.512 7.475 ;
     RECT  14.808 7.475 16.56 8.485 ;
     RECT  11.712 7.715 12.432 9.205 ;
     RECT  8.568 7.813 9.336 7.909 ;
     RECT  9 7.909 9.984 8.531 ;
     RECT  15.432 8.485 16.56 9.299 ;
     RECT  13.512 8.579 13.608 9.637 ;
     RECT  11.4 9.205 12.432 9.251 ;
     RECT  11.4 9.251 13.2 10.021 ;
     RECT  15.984 9.299 16.56 10.117 ;
     RECT  11.976 10.021 13.2 10.883 ;
     RECT  16.104 10.691 17.232 10.883 ;
     RECT  13.512 13.621 14.784 15.445 ;
     RECT  16.872 13.861 18 15.443 ;
     RECT  13.512 15.445 14.688 15.587 ;
  END
END qkd_rstseq
END LIBRARY
